VERSION 5.7 ;
  NOWIREEXTENSIONATPIN ON ;
  DIVIDERCHAR "/" ;
  BUSBITCHARS "[]" ;
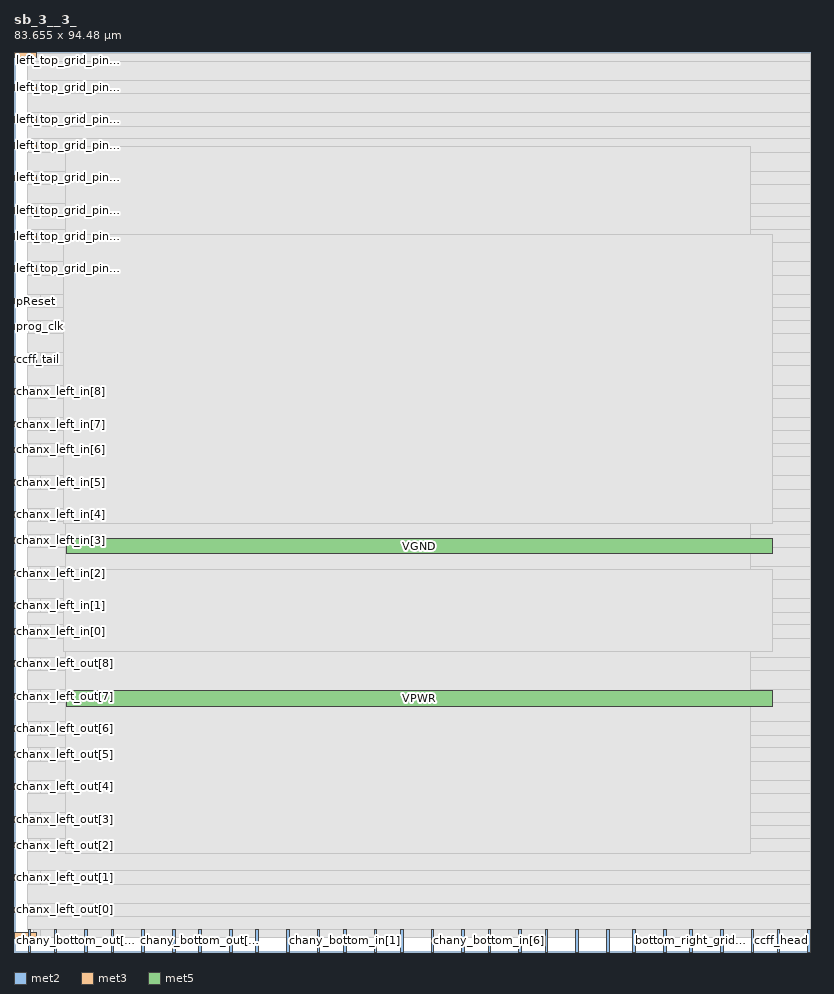
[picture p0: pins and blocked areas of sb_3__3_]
MACRO sb_3__3_
  CLASS BLOCK ;
  FOREIGN sb_3__3_ ;
  ORIGIN 0.000 0.000 ;
  SIZE 83.655 BY 94.480 ;
  PIN bottom_left_grid_pin_13_
    DIRECTION INPUT ;
    PORT
      LAYER met2 ;
        RECT 1.470 0.000 1.750 2.400 ;
    END
  END bottom_left_grid_pin_13_
  PIN bottom_right_grid_pin_11_
    DIRECTION INPUT ;
    PORT
      LAYER met2 ;
        RECT 64.950 0.000 65.230 2.400 ;
    END
  END bottom_right_grid_pin_11_
  PIN bottom_right_grid_pin_13_
    DIRECTION INPUT ;
    PORT
      LAYER met2 ;
        RECT 62.190 0.000 62.470 2.400 ;
    END
  END bottom_right_grid_pin_13_
  PIN bottom_right_grid_pin_15_
    DIRECTION INPUT ;
    PORT
      LAYER met2 ;
        RECT 58.970 0.000 59.250 2.400 ;
    END
  END bottom_right_grid_pin_15_
  PIN bottom_right_grid_pin_1_
    DIRECTION INPUT ;
    PORT
      LAYER met2 ;
        RECT 80.130 0.000 80.410 2.400 ;
    END
  END bottom_right_grid_pin_1_
  PIN bottom_right_grid_pin_3_
    DIRECTION INPUT ;
    PORT
      LAYER met2 ;
        RECT 77.370 0.000 77.650 2.400 ;
    END
  END bottom_right_grid_pin_3_
  PIN bottom_right_grid_pin_5_
    DIRECTION INPUT ;
    PORT
      LAYER met2 ;
        RECT 74.150 0.000 74.430 2.400 ;
    END
  END bottom_right_grid_pin_5_
  PIN bottom_right_grid_pin_7_
    DIRECTION INPUT ;
    PORT
      LAYER met2 ;
        RECT 70.930 0.000 71.210 2.400 ;
    END
  END bottom_right_grid_pin_7_
  PIN bottom_right_grid_pin_9_
    DIRECTION INPUT ;
    PORT
      LAYER met2 ;
        RECT 68.170 0.000 68.450 2.400 ;
    END
  END bottom_right_grid_pin_9_
  PIN ccff_head
    DIRECTION INPUT ;
    PORT
      LAYER met2 ;
        RECT 83.350 0.000 83.630 2.400 ;
    END
  END ccff_head
  PIN ccff_tail
    DIRECTION OUTPUT TRISTATE ;
    PORT
      LAYER met3 ;
        RECT 0.000 61.920 2.400 62.520 ;
    END
  END ccff_tail
  PIN chanx_left_in[0]
    DIRECTION INPUT ;
    PORT
      LAYER met3 ;
        RECT 0.000 33.360 2.400 33.960 ;
    END
  END chanx_left_in[0]
  PIN chanx_left_in[1]
    DIRECTION INPUT ;
    PORT
      LAYER met3 ;
        RECT 0.000 36.080 2.400 36.680 ;
    END
  END chanx_left_in[1]
  PIN chanx_left_in[2]
    DIRECTION INPUT ;
    PORT
      LAYER met3 ;
        RECT 0.000 39.480 2.400 40.080 ;
    END
  END chanx_left_in[2]
  PIN chanx_left_in[3]
    DIRECTION INPUT ;
    PORT
      LAYER met3 ;
        RECT 0.000 42.880 2.400 43.480 ;
    END
  END chanx_left_in[3]
  PIN chanx_left_in[4]
    DIRECTION INPUT ;
    PORT
      LAYER met3 ;
        RECT 0.000 45.600 2.400 46.200 ;
    END
  END chanx_left_in[4]
  PIN chanx_left_in[5]
    DIRECTION INPUT ;
    PORT
      LAYER met3 ;
        RECT 0.000 49.000 2.400 49.600 ;
    END
  END chanx_left_in[5]
  PIN chanx_left_in[6]
    DIRECTION INPUT ;
    PORT
      LAYER met3 ;
        RECT 0.000 52.400 2.400 53.000 ;
    END
  END chanx_left_in[6]
  PIN chanx_left_in[7]
    DIRECTION INPUT ;
    PORT
      LAYER met3 ;
        RECT 0.000 55.120 2.400 55.720 ;
    END
  END chanx_left_in[7]
  PIN chanx_left_in[8]
    DIRECTION INPUT ;
    PORT
      LAYER met3 ;
        RECT 0.000 58.520 2.400 59.120 ;
    END
  END chanx_left_in[8]
  PIN chanx_left_out[0]
    DIRECTION OUTPUT TRISTATE ;
    PORT
      LAYER met3 ;
        RECT 0.000 4.120 2.400 4.720 ;
    END
  END chanx_left_out[0]
  PIN chanx_left_out[1]
    DIRECTION OUTPUT TRISTATE ;
    PORT
      LAYER met3 ;
        RECT 0.000 7.520 2.400 8.120 ;
    END
  END chanx_left_out[1]
  PIN chanx_left_out[2]
    DIRECTION OUTPUT TRISTATE ;
    PORT
      LAYER met3 ;
        RECT 0.000 10.920 2.400 11.520 ;
    END
  END chanx_left_out[2]
  PIN chanx_left_out[3]
    DIRECTION OUTPUT TRISTATE ;
    PORT
      LAYER met3 ;
        RECT 0.000 13.640 2.400 14.240 ;
    END
  END chanx_left_out[3]
  PIN chanx_left_out[4]
    DIRECTION OUTPUT TRISTATE ;
    PORT
      LAYER met3 ;
        RECT 0.000 17.040 2.400 17.640 ;
    END
  END chanx_left_out[4]
  PIN chanx_left_out[5]
    DIRECTION OUTPUT TRISTATE ;
    PORT
      LAYER met3 ;
        RECT 0.000 20.440 2.400 21.040 ;
    END
  END chanx_left_out[5]
  PIN chanx_left_out[6]
    DIRECTION OUTPUT TRISTATE ;
    PORT
      LAYER met3 ;
        RECT 0.000 23.160 2.400 23.760 ;
    END
  END chanx_left_out[6]
  PIN chanx_left_out[7]
    DIRECTION OUTPUT TRISTATE ;
    PORT
      LAYER met3 ;
        RECT 0.000 26.560 2.400 27.160 ;
    END
  END chanx_left_out[7]
  PIN chanx_left_out[8]
    DIRECTION OUTPUT TRISTATE ;
    PORT
      LAYER met3 ;
        RECT 0.000 29.960 2.400 30.560 ;
    END
  END chanx_left_out[8]
  PIN chany_bottom_in[0]
    DIRECTION INPUT ;
    PORT
      LAYER met2 ;
        RECT 31.830 0.000 32.110 2.400 ;
    END
  END chany_bottom_in[0]
  PIN chany_bottom_in[1]
    DIRECTION INPUT ;
    PORT
      LAYER met2 ;
        RECT 34.590 0.000 34.870 2.400 ;
    END
  END chany_bottom_in[1]
  PIN chany_bottom_in[2]
    DIRECTION INPUT ;
    PORT
      LAYER met2 ;
        RECT 37.810 0.000 38.090 2.400 ;
    END
  END chany_bottom_in[2]
  PIN chany_bottom_in[3]
    DIRECTION INPUT ;
    PORT
      LAYER met2 ;
        RECT 40.570 0.000 40.850 2.400 ;
    END
  END chany_bottom_in[3]
  PIN chany_bottom_in[4]
    DIRECTION INPUT ;
    PORT
      LAYER met2 ;
        RECT 43.790 0.000 44.070 2.400 ;
    END
  END chany_bottom_in[4]
  PIN chany_bottom_in[5]
    DIRECTION INPUT ;
    PORT
      LAYER met2 ;
        RECT 47.010 0.000 47.290 2.400 ;
    END
  END chany_bottom_in[5]
  PIN chany_bottom_in[6]
    DIRECTION INPUT ;
    PORT
      LAYER met2 ;
        RECT 49.770 0.000 50.050 2.400 ;
    END
  END chany_bottom_in[6]
  PIN chany_bottom_in[7]
    DIRECTION INPUT ;
    PORT
      LAYER met2 ;
        RECT 52.990 0.000 53.270 2.400 ;
    END
  END chany_bottom_in[7]
  PIN chany_bottom_in[8]
    DIRECTION INPUT ;
    PORT
      LAYER met2 ;
        RECT 55.750 0.000 56.030 2.400 ;
    END
  END chany_bottom_in[8]
  PIN chany_bottom_out[0]
    DIRECTION OUTPUT TRISTATE ;
    PORT
      LAYER met2 ;
        RECT 4.230 0.000 4.510 2.400 ;
    END
  END chany_bottom_out[0]
  PIN chany_bottom_out[1]
    DIRECTION OUTPUT TRISTATE ;
    PORT
      LAYER met2 ;
        RECT 7.450 0.000 7.730 2.400 ;
    END
  END chany_bottom_out[1]
  PIN chany_bottom_out[2]
    DIRECTION OUTPUT TRISTATE ;
    PORT
      LAYER met2 ;
        RECT 10.210 0.000 10.490 2.400 ;
    END
  END chany_bottom_out[2]
  PIN chany_bottom_out[3]
    DIRECTION OUTPUT TRISTATE ;
    PORT
      LAYER met2 ;
        RECT 13.430 0.000 13.710 2.400 ;
    END
  END chany_bottom_out[3]
  PIN chany_bottom_out[4]
    DIRECTION OUTPUT TRISTATE ;
    PORT
      LAYER met2 ;
        RECT 16.650 0.000 16.930 2.400 ;
    END
  END chany_bottom_out[4]
  PIN chany_bottom_out[5]
    DIRECTION OUTPUT TRISTATE ;
    PORT
      LAYER met2 ;
        RECT 19.410 0.000 19.690 2.400 ;
    END
  END chany_bottom_out[5]
  PIN chany_bottom_out[6]
    DIRECTION OUTPUT TRISTATE ;
    PORT
      LAYER met2 ;
        RECT 22.630 0.000 22.910 2.400 ;
    END
  END chany_bottom_out[6]
  PIN chany_bottom_out[7]
    DIRECTION OUTPUT TRISTATE ;
    PORT
      LAYER met2 ;
        RECT 25.390 0.000 25.670 2.400 ;
    END
  END chany_bottom_out[7]
  PIN chany_bottom_out[8]
    DIRECTION OUTPUT TRISTATE ;
    PORT
      LAYER met2 ;
        RECT 28.610 0.000 28.890 2.400 ;
    END
  END chany_bottom_out[8]
  PIN left_bottom_grid_pin_12_
    DIRECTION INPUT ;
    PORT
      LAYER met3 ;
        RECT 0.000 1.400 2.400 2.000 ;
    END
  END left_bottom_grid_pin_12_
  PIN left_top_grid_pin_11_
    DIRECTION INPUT ;
    PORT
      LAYER met3 ;
        RECT 0.000 77.560 2.400 78.160 ;
    END
  END left_top_grid_pin_11_
  PIN left_top_grid_pin_13_
    DIRECTION INPUT ;
    PORT
      LAYER met3 ;
        RECT 0.000 74.840 2.400 75.440 ;
    END
  END left_top_grid_pin_13_
  PIN left_top_grid_pin_15_
    DIRECTION INPUT ;
    PORT
      LAYER met3 ;
        RECT 0.000 71.440 2.400 72.040 ;
    END
  END left_top_grid_pin_15_
  PIN left_top_grid_pin_1_
    DIRECTION INPUT ;
    PORT
      LAYER met3 ;
        RECT 0.000 93.880 2.400 94.480 ;
    END
  END left_top_grid_pin_1_
  PIN left_top_grid_pin_3_
    DIRECTION INPUT ;
    PORT
      LAYER met3 ;
        RECT 0.000 90.480 2.400 91.080 ;
    END
  END left_top_grid_pin_3_
  PIN left_top_grid_pin_5_
    DIRECTION INPUT ;
    PORT
      LAYER met3 ;
        RECT 0.000 87.080 2.400 87.680 ;
    END
  END left_top_grid_pin_5_
  PIN left_top_grid_pin_7_
    DIRECTION INPUT ;
    PORT
      LAYER met3 ;
        RECT 0.000 84.360 2.400 84.960 ;
    END
  END left_top_grid_pin_7_
  PIN left_top_grid_pin_9_
    DIRECTION INPUT ;
    PORT
      LAYER met3 ;
        RECT 0.000 80.960 2.400 81.560 ;
    END
  END left_top_grid_pin_9_
  PIN pReset
    DIRECTION INPUT ;
    PORT
      LAYER met3 ;
        RECT 0.000 68.040 2.400 68.640 ;
    END
  END pReset
  PIN prog_clk
    DIRECTION INPUT ;
    PORT
      LAYER met3 ;
        RECT 0.000 65.320 2.400 65.920 ;
    END
  END prog_clk
  PIN VPWR
    DIRECTION INPUT ;
    USE POWER ;
    PORT
      LAYER met5 ;
        RECT 5.520 25.820 79.580 27.420 ;
    END
  END VPWR
  PIN VGND
    DIRECTION INPUT ;
    USE GROUND ;
    PORT
      LAYER met5 ;
        RECT 5.520 41.800 79.580 43.400 ;
    END
  END VGND
  OBS
      LAYER li1 ;
        RECT 5.520 10.795 79.580 84.405 ;
      LAYER met1 ;
        RECT 5.520 2.760 79.580 84.960 ;
      LAYER met2 ;
        RECT 1.470 2.680 83.630 94.365 ;
        RECT 2.030 1.515 3.950 2.680 ;
        RECT 4.790 1.515 7.170 2.680 ;
        RECT 8.010 1.515 9.930 2.680 ;
        RECT 10.770 1.515 13.150 2.680 ;
        RECT 13.990 1.515 16.370 2.680 ;
        RECT 17.210 1.515 19.130 2.680 ;
        RECT 19.970 1.515 22.350 2.680 ;
        RECT 23.190 1.515 25.110 2.680 ;
        RECT 25.950 1.515 28.330 2.680 ;
        RECT 29.170 1.515 31.550 2.680 ;
        RECT 32.390 1.515 34.310 2.680 ;
        RECT 35.150 1.515 37.530 2.680 ;
        RECT 38.370 1.515 40.290 2.680 ;
        RECT 41.130 1.515 43.510 2.680 ;
        RECT 44.350 1.515 46.730 2.680 ;
        RECT 47.570 1.515 49.490 2.680 ;
        RECT 50.330 1.515 52.710 2.680 ;
        RECT 53.550 1.515 55.470 2.680 ;
        RECT 56.310 1.515 58.690 2.680 ;
        RECT 59.530 1.515 61.910 2.680 ;
        RECT 62.750 1.515 64.670 2.680 ;
        RECT 65.510 1.515 67.890 2.680 ;
        RECT 68.730 1.515 70.650 2.680 ;
        RECT 71.490 1.515 73.870 2.680 ;
        RECT 74.710 1.515 77.090 2.680 ;
        RECT 77.930 1.515 79.850 2.680 ;
        RECT 80.690 1.515 83.070 2.680 ;
      LAYER met3 ;
        RECT 2.800 93.480 83.655 94.345 ;
        RECT 1.445 91.480 83.655 93.480 ;
        RECT 2.800 90.080 83.655 91.480 ;
        RECT 1.445 88.080 83.655 90.080 ;
        RECT 2.800 86.680 83.655 88.080 ;
        RECT 1.445 85.360 83.655 86.680 ;
        RECT 2.800 83.960 83.655 85.360 ;
        RECT 1.445 81.960 83.655 83.960 ;
        RECT 2.800 80.560 83.655 81.960 ;
        RECT 1.445 78.560 83.655 80.560 ;
        RECT 2.800 77.160 83.655 78.560 ;
        RECT 1.445 75.840 83.655 77.160 ;
        RECT 2.800 74.440 83.655 75.840 ;
        RECT 1.445 72.440 83.655 74.440 ;
        RECT 2.800 71.040 83.655 72.440 ;
        RECT 1.445 69.040 83.655 71.040 ;
        RECT 2.800 67.640 83.655 69.040 ;
        RECT 1.445 66.320 83.655 67.640 ;
        RECT 2.800 64.920 83.655 66.320 ;
        RECT 1.445 62.920 83.655 64.920 ;
        RECT 2.800 61.520 83.655 62.920 ;
        RECT 1.445 59.520 83.655 61.520 ;
        RECT 2.800 58.120 83.655 59.520 ;
        RECT 1.445 56.120 83.655 58.120 ;
        RECT 2.800 54.720 83.655 56.120 ;
        RECT 1.445 53.400 83.655 54.720 ;
        RECT 2.800 52.000 83.655 53.400 ;
        RECT 1.445 50.000 83.655 52.000 ;
        RECT 2.800 48.600 83.655 50.000 ;
        RECT 1.445 46.600 83.655 48.600 ;
        RECT 2.800 45.200 83.655 46.600 ;
        RECT 1.445 43.880 83.655 45.200 ;
        RECT 2.800 42.480 83.655 43.880 ;
        RECT 1.445 40.480 83.655 42.480 ;
        RECT 2.800 39.080 83.655 40.480 ;
        RECT 1.445 37.080 83.655 39.080 ;
        RECT 2.800 35.680 83.655 37.080 ;
        RECT 1.445 34.360 83.655 35.680 ;
        RECT 2.800 32.960 83.655 34.360 ;
        RECT 1.445 30.960 83.655 32.960 ;
        RECT 2.800 29.560 83.655 30.960 ;
        RECT 1.445 27.560 83.655 29.560 ;
        RECT 2.800 26.160 83.655 27.560 ;
        RECT 1.445 24.160 83.655 26.160 ;
        RECT 2.800 22.760 83.655 24.160 ;
        RECT 1.445 21.440 83.655 22.760 ;
        RECT 2.800 20.040 83.655 21.440 ;
        RECT 1.445 18.040 83.655 20.040 ;
        RECT 2.800 16.640 83.655 18.040 ;
        RECT 1.445 14.640 83.655 16.640 ;
        RECT 2.800 13.240 83.655 14.640 ;
        RECT 1.445 11.920 83.655 13.240 ;
        RECT 2.800 10.520 83.655 11.920 ;
        RECT 1.445 8.520 83.655 10.520 ;
        RECT 2.800 7.120 83.655 8.520 ;
        RECT 1.445 5.120 83.655 7.120 ;
        RECT 2.800 3.720 83.655 5.120 ;
        RECT 1.445 2.400 83.655 3.720 ;
        RECT 2.800 1.535 83.655 2.400 ;
      LAYER met4 ;
        RECT 5.390 10.375 77.285 84.560 ;
      LAYER met5 ;
        RECT 5.180 45.000 79.580 75.360 ;
        RECT 5.180 31.500 79.580 40.200 ;
  END
END sb_3__3_
END LIBRARY

